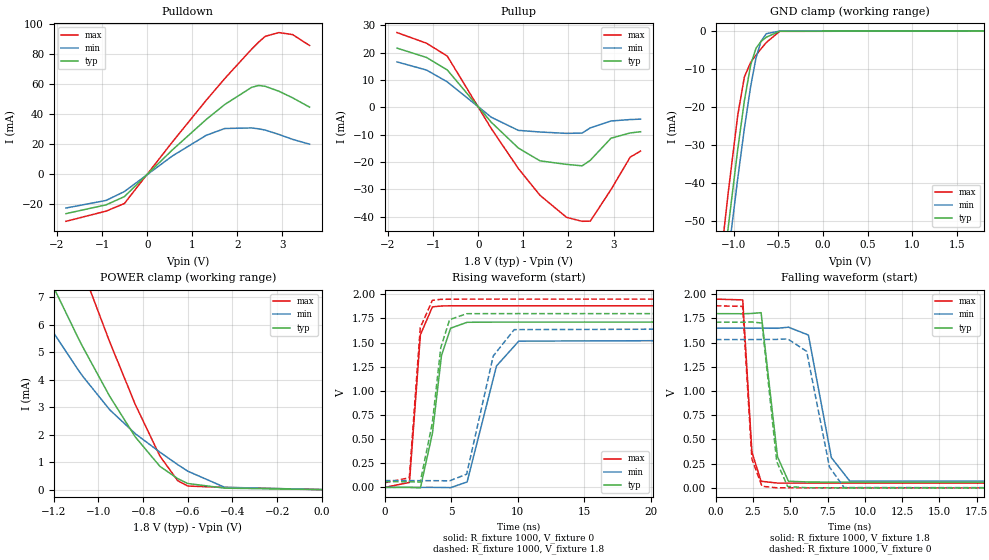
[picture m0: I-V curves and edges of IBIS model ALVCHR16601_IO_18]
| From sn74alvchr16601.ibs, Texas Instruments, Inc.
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[Model]   ALVCHR16601_IO_18
Model_type  I/O
Vinl=0.5775
Vinh=1.2675
Enable   Active-Low
Vref =   0
Rref =   1000
Cref =   30p
Vmeas =   0.9
| variable   typ   min   max
C_comp   8.44pF   7.09pF   9.28pF
| C_pullup   7.53pF   5.48pF   9.59pF
| C_pulldown   6.03pF   5.18pF   6.85pF
| C_tri-state   8.44pF   7.09pF   9.28pF
[Temperature Range]   40   100   -40
| Ambient temperature   25   85   -40
[Voltage range]   1.8   1.65   1.95
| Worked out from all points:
|   slope of the pulldown table from 0 to 0.27 V, typ, clamps not added: 34.2 ohm
|   slope of the pullup table from 0 to 0.27 V, typ, clamps not added: 53.3 ohm
|   GND clamp passes 1 mA (typ) near -0.59 V on its own axis
|   POWER clamp passes 1 mA (typ) near -0.74 V on its own axis
|   rising waveform, R_fixture 1000, V_fixture 0: 20-80 % time 839ps typ, 1.56ns min, 492ps max; typ from 0 V to 1.71 V
|   falling waveform, R_fixture 1000, V_fixture 1.8: 20-80 % time 577ps typ, 1.02ns min, 361ps max; typ from 1.8 V to 0.059 V
|   rising waveform, R_fixture 1000, V_fixture 1.8: 20-80 % time 809ps typ, 1.44ns min, 484ps max; typ from 0.059 V to 1.8 V
|   falling waveform, R_fixture 1000, V_fixture 0: 20-80 % time 575ps typ, 1.05ns min, 357ps max; typ from 1.71 V to 0 V
[GND Clamp]
| ALVCHR16601_IO_18
|   Voltage   I(typ)   I(min)   I(max)
-1.8V     -209.4mA   -212.3mA   -207mA
-1.145V   -68.53mA   -75.51mA   -60.04mA
-1.105V   -60.37mA   -67.56mA   -51.56mA
-1.06V    -51.33mA   -58.73mA   -42.24mA
-955mV    -31.16mA   -38.82mA   -22.2mA
-880mV    -18.29mA   -25.57mA   -12.07mA
-810mV    -8.944mA   -14.57mA   -8.27mA
-750mV    -4.548mA   -7.1mA     -6.37mA
-695mV    -2.807mA   -2.776mA   -4.74mA
-635mV    -1.675mA   -743.3uA   -3.057mA
-485mV    -88.56uA   -64.59uA   -131.8uA
1.8V      63.55pA    9.524uA    -22.72uA
[POWER Clamp]
| ALVCHR16601_IO_18
|   Voltage   I(typ)   I(min)   I(max)
-1.8V     18.69mA    14.41mA    25.98mA
-1.405V   10.98mA    8.42mA     15.85mA
-1.26V    8.365mA    6.439mA    12.34mA
-1.09V    5.509mA    4.349mA    8.415mA
-1.07V    5.193mA    4.125mA    7.969mA
-950mV    3.402mA    2.911mA    5.387mA
-835mV    1.918mA    2.037mA    3.098mA
-725mV    848.2uA    1.366mA    1.223mA
-645mV    399.6uA    909.3uA    324.6uA
-600mV    222.4uA    671uA      129.5uA
-435mV    53uA       84.87uA    78.91uA
-16.28fV  63.55pA    285.5pA    36.64pA
[Pulldown]
| ALVCHR16601_IO_18
|   Voltage   I(typ)   I(min)   I(max)
-1.8V     -26.28mA   -22.55mA   -31.39mA
-910mV    -20.44mA   -17.49mA   -24.62mA
-505mV    -14.95mA   -11.58mA   -19.53mA
555mV     16.04mA    12.03mA    21.3mA
1.31V     36.42mA    25.88mA    49.21mA
1.72V     46.37mA    30.39mA    63.64mA
2.315V    57.78mA    30.76mA    83.17mA
2.47V     59.02mA    30.16mA    87.86mA
2.62V     58.43mA    29.32mA    91.76mA
2.92V     55.19mA    26.44mA    94.24mA
3.225V    50.8mA     23.14mA    92.88mA
3.6V      44.6mA     19.95mA    85.64mA
[Pullup]
| ALVCHR16601_IO_18
|   Voltage   I(typ)   I(min)   I(max)
-1.8V     21.67mA    16.64mA    27.36mA
-1.145V   18.26mA    13.65mA    23.46mA
-685mV    13.68mA    9.322mA    18.75mA
290mV     -5.425mA   -3.589mA   -7.737mA
890mV     -14.85mA   -8.397mA   -22.34mA
1.37V     -19.54mA   -8.99mA    -32.13mA
1.96V     -20.83mA   -9.497mA   -40.21mA
2.305V    -21.36mA   -9.38mA    -41.64mA
2.485V    -19.34mA   -7.488mA   -41.58mA
2.945V    -11.26mA   -4.959mA   -30.04mA
3.37V     -9.339mA   -4.441mA   -18.18mA
3.6V      -8.895mA   -4.293mA   -15.96mA
[Ramp]
| ALVCHR16601_IO_18
| variable   typ   min   max
dV/dt_r   1.03/8.88E-10   0.92/1.64E-09   1.13/5.24E-10
dV/dt_f   1.06/6.04E-10   0.96/1.05E-09   1.15/3.80E-10
R_load = 1000
[Rising Waveform]
| ALVCHR16601_IO_18
R_fixture =   1000
C_fixture =   0
L_fixture =   0
V_fixture =   0
V_fixture_min = 0
V_fixture_max = 0
|   Time   V(typ)   V(min)   V(max)
0s        90.74uV    129.1uV    66.41uV
1.85ns    -257.9uV   518.5uV    51.27mV
2.675ns   -4.987mV   -48.17uV   1.582V
3.58ns    562mV      121uV      1.87V
4.26ns    1.367V     -712.6uV   1.879V
4.945ns   1.649V     -2.892mV   1.881V
6.185ns   1.71V      55.73mV    1.881V
8.395ns   1.712V     1.258V     1.881V
10.07ns   1.712V     1.515V     1.881V
49.99ns   1.712V     1.532V     1.881V
[Falling Waveform]
| ALVCHR16601_IO_18
R_fixture =   1000
C_fixture =   0
L_fixture =   0
V_fixture =   1.8
V_fixture_min = 1.65
V_fixture_max = 1.95
|   Time   V(typ)   V(min)   V(max)
0s        1.8V       1.65V      1.95V
1.805ns   1.799V     1.65V      1.942V
2.42ns    1.802V     1.649V     368.9mV
3.035ns   1.81V      1.65V      68.35mV
4.135ns   322.2mV    1.649V     49.61mV
4.87ns    68.11mV    1.66V      48.99mV
6.21ns    60.68mV    1.579V     48.8mV
7.75ns    58.99mV    312.3mV    48.75mV
8.985ns   58.98mV    69.9mV     48.75mV
49.99ns   59.05mV    70.32mV    48.81mV
[Rising Waveform]
| ALVCHR16601_IO_18
R_fixture =   1000
C_fixture =   0
L_fixture =   0
V_fixture =   1.8
V_fixture_min = 1.65
V_fixture_max = 1.95
|   Time   V(typ)   V(min)   V(max)
0s        58.99mV    70.24mV    48.79mV
1.84ns    58.22mV    70.17mV    98.95mV
2.665ns   55.13mV    69.46mV    1.655V
3.575ns   672.1mV    69.45mV    1.938V
4.205ns   1.448V     68.96mV    1.948V
4.87ns    1.737V     68.1mV     1.949V
6.15ns    1.799V     136.6mV    1.95V
8.15ns    1.8V       1.361V     1.95V
9.725ns   1.8V       1.634V     1.95V
49.99ns   1.8V       1.65V      1.95V
[Falling Waveform]
| ALVCHR16601_IO_18
R_fixture =   1000
C_fixture =   0
L_fixture =   0
V_fixture =   0
V_fixture_min = 0
V_fixture_max = 0
|   Time   V(typ)   V(min)   V(max)
0s        1.712V     1.532V     1.881V
1.795ns   1.711V     1.532V     1.875V
2.42ns    1.714V     1.532V     298.3mV
3.095ns   1.703V     1.533V     16.3mV
4.085ns   271.9mV    1.534V     821.8uV
4.815ns   14.15mV    1.539V     226uV
6.09ns    1.409mV    1.411V     40.07uV
7.62ns    28.45uV    216.1mV    5.941uV
8.6ns     20.33uV    2.876mV    3.211uV
49.99ns   98.99uV    133.4uV    71.12uV
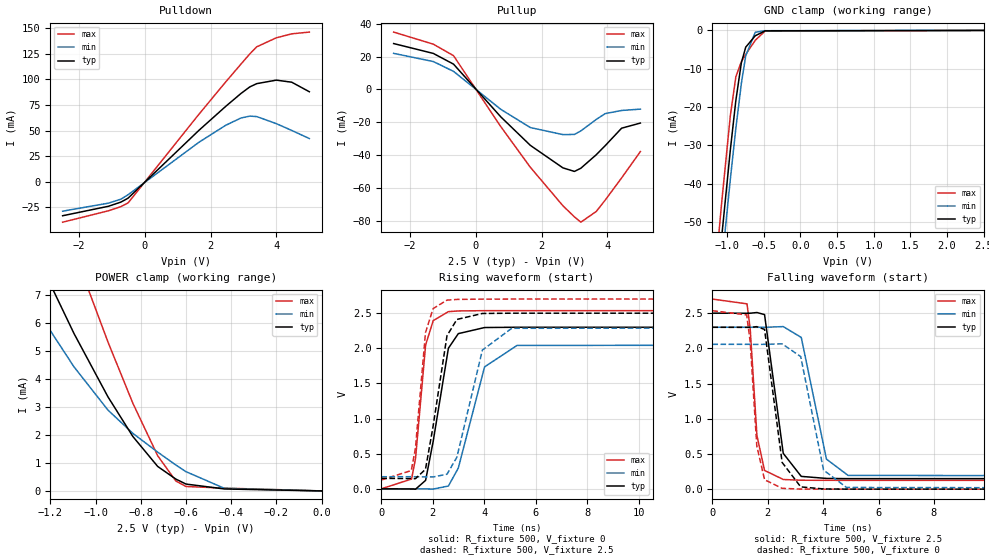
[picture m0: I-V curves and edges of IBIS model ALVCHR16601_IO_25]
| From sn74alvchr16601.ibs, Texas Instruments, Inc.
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[Model]   ALVCHR16601_IO_25
Model_type  I/O
Vinl=0.7
Vinh=1.7
Enable   Active-Low
Vref =   0
Rref =   500
Cref =   30p
Vmeas =   1.25
| variable   typ   min   max
C_comp   8.22pF   6.73pF   9.22pF
| C_pullup   6.53pF   4.92pF   9.23pF
| C_pulldown   5.50pF   4.65pF   6.40pF
| C_tri-state   8.22pF   6.73pF   9.22pF
[Temperature Range]   40   100   -40
| Ambient temperature   25   85   -40
[Voltage range]   2.5   2.3   2.7
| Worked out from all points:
|   slope of the pulldown table from 0 to 0.375 V, typ, clamps not added: 32 ohm
|   slope of the pullup table from 0 to 0.375 V, typ, clamps not added: 44.3 ohm
|   GND clamp passes 1 mA (typ) near -0.59 V on its own axis
|   POWER clamp passes 1 mA (typ) near -0.74 V on its own axis
|   rising waveform, R_fixture 500, V_fixture 0: 20-80 % time 547ps typ, 826ps min, 363ps max; typ from 0 V to 2.3 V
|   falling waveform, R_fixture 500, V_fixture 2.5: 20-80 % time 383ps typ, 582ps min, 262ps max; typ from 2.5 V to 0.149 V
|   rising waveform, R_fixture 500, V_fixture 2.5: 20-80 % time 533ps typ, 779ps min, 358ps max; typ from 0.149 V to 2.5 V
|   falling waveform, R_fixture 500, V_fixture 0: 20-80 % time 379ps typ, 560ps min, 261ps max; typ from 2.3 V to 0 V
[GND Clamp]
| ALVCHR16601_IO_25
|   Voltage   I(typ)   I(min)   I(max)
-2.5V     -365.2mA   -363.7mA   -369.1mA
-1.165V   -72.71mA   -79.57mA   -64.41mA
-1.13V    -65.52mA   -72.56mA   -56.92mA
-1.1V     -59.41mA   -66.61mA   -50.59mA
-1.07V    -53.37mA   -60.72mA   -44.35mA
-955mV    -31.21mA   -38.86mA   -22.26mA
-880mV    -18.33mA   -25.6mA    -12.12mA
-805mV    -8.478mA   -13.89mA   -8.152mA
-745mV    -4.368mA   -6.626mA   -6.27mA
-615mV    -1.393mA   -469.9uA   -2.576mA
-480mV    -112.9uA   -83.35uA   -159.6uA
2.5V      87.99pA    20.8uA     -42.68uA
[POWER Clamp]
| ALVCHR16601_IO_25
|   Voltage   I(typ)   I(min)   I(max)
-2.5V     33.67mA    26.3mA     45.27mA
-1.415V   11.21mA    8.594mA    16.15mA
-1.39V    10.75mA    8.24mA     15.54mA
-1.265V   8.491mA    6.534mA    12.51mA
-1.095V   5.624mA    4.433mA    8.571mA
-945mV    3.363mA    2.89mA     5.323mA
-835mV    1.947mA    2.059mA    3.136mA
-725mV    874.4uA    1.386mA    1.257mA
-645mV    424.2uA    927.8uA    355.8uA
-600mV    245.9uA    688.6uA    159.1uA
-430mV    70.36uA    92.66uA    100.4uA
-31.15fV  87.99pA    322.5pA    50.89pA
[Pulldown]
| ALVCHR16601_IO_25
|   Voltage   I(typ)   I(min)   I(max)
-2.5V     -33.12mA   -28.66mA   -39.41mA
-1.105V   -23.86mA   -20.81mA   -28.26mA
-730mV    -19.83mA   -16.99mA   -24.25mA
-510mV    -15.98mA   -12.64mA   -20.61mA
1.64V     50.12mA    38.5mA     65.78mA
2.46V     73.66mA    55.21mA    97.52mA
2.925V    86.28mA    62.29mA    115mA
3.19V     92.61mA    64.1mA     124.8mA
3.4V      95.78mA    63.66mA    131.7mA
3.995V    99.21mA    56.79mA    140.5mA
4.465V    97.19mA    50.11mA    144.4mA
5V        87.89mA    42.22mA    146.1mA
[Pullup]
| ALVCHR16601_IO_25
|   Voltage   I(typ)   I(min)   I(max)
-2.5V     27.94mA    21.97mA    34.92mA
-1.295V   21.94mA    16.99mA    27.57mA
-680mV    15.41mA    11.02mA    20.57mA
760mV     -16.74mA   -12.15mA   -22.7mA
1.655V    -34.02mA   -23.19mA   -47.37mA
2.645V    -47.72mA   -27.48mA   -70.78mA
2.995V    -49.89mA   -27.37mA   -77.55mA
3.19V     -47.96mA   -25.25mA   -80.79mA
3.66V     -39.71mA   -18.23mA   -74.24mA
3.93V     -34.22mA   -14.7mA    -67.37mA
4.43V     -23.57mA   -12.79mA   -53.83mA
5V        -20.46mA   -11.98mA   -37.8mA
[Ramp]
| ALVCHR16601_IO_25
| variable   typ   min   max
dV/dt_r   1.38/5.64E-10   1.24/8.89E-10   1.52/3.72E-10
dV/dt_f   1.42/4.04E-10   1.29/6.09E-10   1.55/2.69E-10
R_load = 500
[Rising Waveform]
| ALVCHR16601_IO_25
R_fixture =   500
C_fixture =   0
L_fixture =   0
V_fixture =   0
V_fixture_min = 0
V_fixture_max = 0
|   Time   V(typ)   V(min)   V(max)
0s        86.33uV    132.2uV    71.62uV
1.175ns   -2.583mV   1.031mV    139.5mV
1.33ns    -4.784mV   637.2uV    435mV
1.72ns    120.5mV    -1.317mV   2.046V
2.015ns   677.3mV    -3.234mV   2.393V
2.605ns   2V         40.06mV    2.521V
2.99ns    2.208V     295.2mV    2.531V
4.01ns    2.295V     1.735V     2.535V
5.27ns    2.299V     2.04V      2.535V
49.99ns   2.299V     2.057V     2.535V
[Falling Waveform]
| ALVCHR16601_IO_25
R_fixture =   500
C_fixture =   0
L_fixture =   0
V_fixture =   2.5
V_fixture_min = 2.3
V_fixture_max = 2.7
|   Time   V(typ)   V(min)   V(max)
0s        2.5V       2.3V       2.7V
1.25ns    2.498V     2.3V       2.632V
1.365ns   2.499V     2.299V     2.286V
1.61ns    2.509V     2.299V     759.7mV
1.885ns   2.479V     2.299V     266.5mV
2.56ns    508.4mV    2.309V     137.6mV
3.21ns    181.5mV    2.155V     126.8mV
4.12ns    152.5mV    426.3mV    125.8mV
4.9ns     149.6mV    195.7mV    125.5mV
49.99ns   149.2mV    172.3mV    125.5mV
[Rising Waveform]
| ALVCHR16601_IO_25
R_fixture =   500
C_fixture =   0
L_fixture =   0
V_fixture =   2.5
V_fixture_min = 2.3
V_fixture_max = 2.7
|   Time   V(typ)   V(min)   V(max)
0s        149.1mV    172.2mV    125.5mV
1.165ns   146.3mV    172.4mV    260.6mV
1.325ns   144.5mV    171.8mV    575.2mV
1.715ns   277.6mV    169.8mV    2.221V
2.01ns    887.8mV    168.6mV    2.564V
2.55ns    2.178V     208.2mV    2.685V
2.935ns   2.41V      449.7mV    2.695V
3.925ns   2.495V     1.974V     2.699V
5.065ns   2.499V     2.284V     2.7V
49.99ns   2.5V       2.3V       2.7V
[Falling Waveform]
| ALVCHR16601_IO_25
R_fixture =   500
C_fixture =   0
L_fixture =   0
V_fixture =   0
V_fixture_min = 0
V_fixture_max = 0
|   Time   V(typ)   V(min)   V(max)
0s        2.299V     2.057V     2.535V
1.24ns    2.298V     2.057V     2.475V
1.365ns   2.299V     2.057V     2.094V
1.605ns   2.308V     2.056V     613.3mV
1.885ns   2.269V     2.057V     134.2mV
2.52ns    379.4mV    2.064V     11.89mV
3.19ns    32.65mV    1.883V     1.141mV
4.015ns   3.261mV    271.7mV    291.9uV
4.845ns   478.2uV    23.95mV    58.67uV
49.99ns   94.87uV    129.7uV    71.4uV
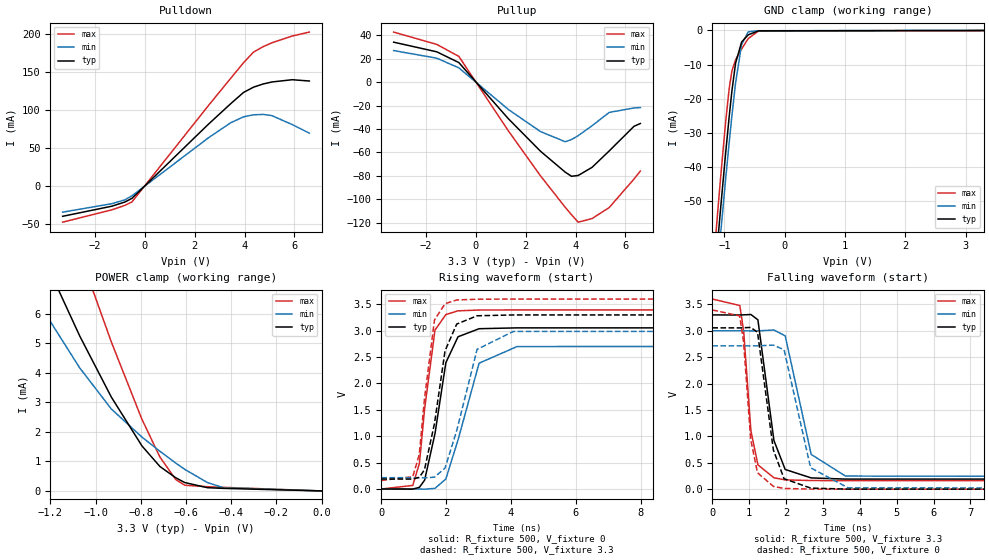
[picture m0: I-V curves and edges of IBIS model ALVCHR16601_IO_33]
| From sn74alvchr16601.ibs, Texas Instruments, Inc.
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[Model]   ALVCHR16601_IO_33
Model_type  I/O
Vinl=0.8
Vinh=2.0
Enable   Active-Low
Vref =   0
Rref =   500
Cref =   50p
Vmeas =   1.5
| variable   typ   min   max
C_comp   8.01pF   6.51pF   9.17pF
| C_pullup   5.95pF   4.54pF   8.13pF
| C_pulldown   5.27pF   4.31pF   6.40pF
| C_tri-state   8.01pF   6.51pF   9.17pF
[Temperature Range]   40   100   -40
| Ambient temperature   25   85   -40
[Voltage range]   3.3   3   3.6
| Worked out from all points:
|   slope of the pulldown table from 0 to 0.495 V, typ, clamps not added: 30.8 ohm
|   slope of the pullup table from 0 to 0.495 V, typ, clamps not added: 40.6 ohm
|   GND clamp passes 1 mA (typ) near -0.59 V on its own axis
|   POWER clamp passes 1 mA (typ) near -0.74 V on its own axis
|   rising waveform, R_fixture 500, V_fixture 0: 20-80 % time 459ps typ, 621ps min, 327ps max; typ from 0 V to 3.06 V
|   falling waveform, R_fixture 500, V_fixture 3.3: 20-80 % time 309ps typ, 435ps min, 235ps max; typ from 3.3 V to 0.19 V
|   rising waveform, R_fixture 500, V_fixture 3.3: 20-80 % time 445ps typ, 600ps min, 323ps max; typ from 0.19 V to 3.3 V
|   falling waveform, R_fixture 500, V_fixture 0: 20-80 % time 310ps typ, 429ps min, 236ps max; typ from 3.06 V to 0 V
[GND Clamp]
| ALVCHR16601_IO_33
|   Voltage   I(typ)   I(min)   I(max)
-3.3V     -545.3mA   -538.8mA   -556.3mA
-1.14V    -67.62mA   -74.6mA    -59.12mA
-1.1V     -59.46mA   -66.65mA   -50.65mA
-1.065V   -52.42mA   -59.78mA   -43.39mA
-980mV    -35.9mA    -43.52mA   -26.75mA
-920mV    -25mA      -32.57mA   -16.84mA
-875mV    -17.59mA   -24.79mA   -11.75mA
-815mV    -9.556mA   -15.35mA   -8.553mA
-715mV    -3.378mA   -4.09mA    -5.422mA
-605mV    -1.273mA   -386uA     -2.362mA
-435mV    -115.8uA   -85.44uA   -163.9uA
3.3V      119.8pA    41.63uA    -79.23uA
[POWER Clamp]
| ALVCHR16601_IO_33
|   Voltage   I(typ)   I(min)   I(max)
-3.3V     51.89mA    40.92mA    68.53mA
-1.375V   10.51mA    8.056mA    15.22mA
-1.24V    8.087mA    6.232mA    11.96mA
-1.07V    5.257mA    4.174mA    8.053mA
-930mV    3.182mA    2.778mA    5.051mA
-795mV    1.53mA     1.827mA    2.434mA
-715mV    826.5uA    1.343mA    1.146mA
-645mV    445.7uA    943.2uA    384uA
-605mV    283uA      729.2uA    192.5uA
-505mV    109.7uA    283.1uA    142.3uA
-435mV    86.92uA    111.2uA    121.7uA
-48.03fV  119.8pA    365.8pA    68.2pA
[Pulldown]
| ALVCHR16601_IO_33
|   Voltage   I(typ)   I(min)   I(max)
-3.3V     -40.46mA   -35mA      -48.24mA
-1.325V   -27.13mA   -23.81mA   -31.95mA
-795mV    -21.53mA   -18.67mA   -25.95mA
-515mV    -16.68mA   -13.33mA   -21.39mA
2.53V     80.5mA     62.69mA    104.9mA
3.45V     108.4mA    83.21mA    142mA
3.96V     123.1mA    90.86mA    162.3mA
4.355V    130mA      93.57mA    176.3mA
4.75V     134.3mA    94.08mA    183.6mA
5.095V    136.9mA    92.55mA    188.6mA
5.915V    139.9mA    80.63mA    197.6mA
6.6V      138.2mA    69.32mA    202.8mA
[Pullup]
| ALVCHR16601_IO_33
|   Voltage   I(typ)   I(min)   I(max)
-3.3V     34.08mA    26.91mA    42.69mA
-1.57V    25.85mA    20.43mA    32.18mA
-685mV    16.68mA    12.17mA    21.96mA
1.305V    -31.33mA   -23.43mA   -41.69mA
2.595V    -59.08mA   -42.27mA   -80.12mA
3.585V    -76.89mA   -50.9mA    -106.9mA
3.835V    -80.4mA    -49.09mA   -113.2mA
4.105V    -79.7mA    -45.72mA   -119.6mA
4.66V     -72.81mA   -37.28mA   -116.5mA
5.35V     -58.76mA   -25.88mA   -107.1mA
6.345V    -37.72mA   -22.07mA   -82.72mA
6.6V      -35.34mA   -21.74mA   -75.92mA
[Ramp]
| ALVCHR16601_IO_33
| variable   typ   min   max
dV/dt_r   1.84/4.72E-10   1.63/6.53E-10   2.04/3.34E-10
dV/dt_f   1.87/3.13E-10   1.68/4.46E-10   2.07/2.41E-10
R_load = 500
[Rising Waveform]
| ALVCHR16601_IO_33
R_fixture =   500
C_fixture =   0
L_fixture =   0
V_fixture =   0
V_fixture_min = 0
V_fixture_max = 0
|   Time   V(typ)   V(min)   V(max)
0s        94.36uV    203.2uV    72.57uV
970ps     -2.185mV   1.419mV    67.71mV
1.175ns   31.79mV    -979uV     485.4mV
1.335ns   167.5mV    -3.34mV    1.516V
1.655ns   1.048V     12.05mV    3.012V
1.99ns    2.393V     189.8mV    3.306V
2.365ns   2.885V     927.4mV    3.377V
3.015ns   3.038V     2.384V     3.392V
4.185ns   3.054V     2.7V       3.394V
49.99ns   3.055V     2.714V     3.394V
[Falling Waveform]
| ALVCHR16601_IO_33
R_fixture =   500
C_fixture =   0
L_fixture =   0
V_fixture =   3.3
V_fixture_min = 3
V_fixture_max = 3.6
|   Time   V(typ)   V(min)   V(max)
0s        3.3V       3V         3.6V
745ps     3.298V     2.999V     3.478V
850ps     3.301V     2.999V     2.984V
1.045ns   3.308V     2.998V     1.108V
1.235ns   3.207V     2.998V     461.2mV
1.67ns    921.4mV    3.014V     215.5mV
1.975ns   372.9mV    2.904V     176.1mV
2.68ns    213.3mV    658mV      163.4mV
3.61ns    191mV      248mV      162.3mV
49.99ns   189.8mV    214.9mV    162.2mV
[Rising Waveform]
| ALVCHR16601_IO_33
R_fixture =   500
C_fixture =   0
L_fixture =   0
V_fixture =   3.3
V_fixture_min = 3
V_fixture_max = 3.6
|   Time   V(typ)   V(min)   V(max)
0s        189.8mV    214.6mV    162.2mV
970ps     187.5mV    215.1mV    232.8mV
1.17ns    221.6mV    212.5mV    652.8mV
1.33ns    361.9mV    210.4mV    1.706V
1.64ns    1.243V     223.8mV    3.205V
1.965ns   2.619V     396.4mV    3.511V
2.325ns   3.126V     1.106V     3.583V
2.955ns   3.283V     2.647V     3.597V
4.07ns    3.299V     2.986V     3.6V
49.99ns   3.3V       3V         3.6V
[Falling Waveform]
| ALVCHR16601_IO_33
R_fixture =   500
C_fixture =   0
L_fixture =   0
V_fixture =   0
V_fixture_min = 0
V_fixture_max = 0
|   Time   V(typ)   V(min)   V(max)
0s        3.055V     2.714V     3.394V
740ps     3.054V     2.714V     3.281V
845ps     3.057V     2.714V     2.798V
1.04ns    3.063V     2.714V     939.2mV
1.225ns   2.971V     2.714V     310mV
1.655ns   741.7mV    2.728V     52.45mV
1.945ns   197.9mV    2.638V     13.7mV
2.665ns   20.58mV    404.7mV    1.104mV
3.68ns    840uV      25.61mV    145.6uV
49.99ns   94.25uV    124uV      70.55uV
